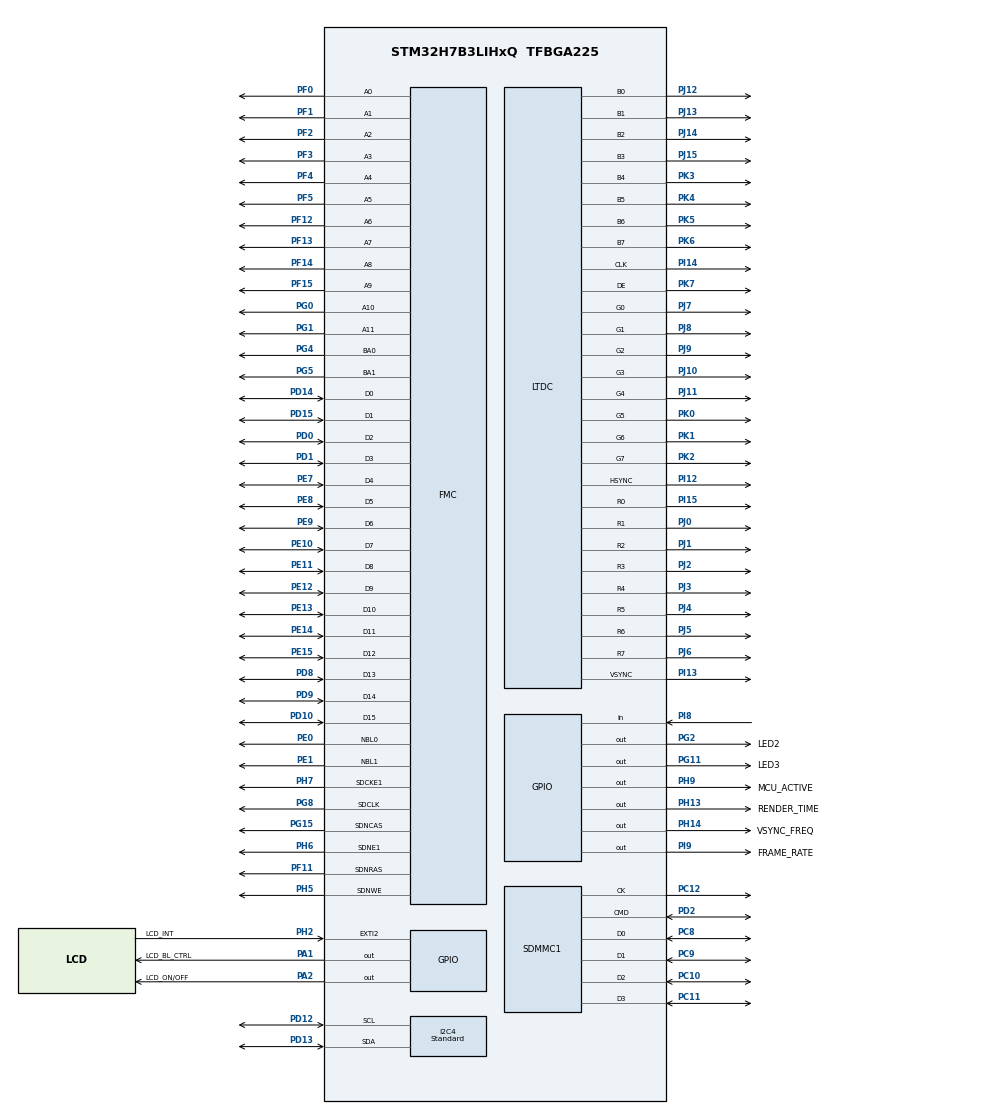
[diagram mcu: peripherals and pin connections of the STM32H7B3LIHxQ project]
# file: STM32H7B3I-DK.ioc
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CORTEX_M7.AccessPermission-Cortex_Memory_Protection_Unit_Region1_Settings=MPU_REGION_FULL_ACCESS
CORTEX_M7.AccessPermission-Cortex_Memory_Protection_Unit_Region2_Settings=MPU_REGION_FULL_ACCESS
CORTEX_M7.AccessPermission-Cortex_Memory_Protection_Unit_Region3_Settings=MPU_REGION_FULL_ACCESS
CORTEX_M7.BaseAddress-Cortex_Memory_Protection_Unit_Region0_Settings=0x90000000
CORTEX_M7.BaseAddress-Cortex_Memory_Protection_Unit_Region1_Settings=0x90000000
CORTEX_M7.BaseAddress-Cortex_Memory_Protection_Unit_Region2_Settings=0x24000000
CORTEX_M7.BaseAddress-Cortex_Memory_Protection_Unit_Region3_Settings=0x24000000
CORTEX_M7.CPU_DCache=Enabled
CORTEX_M7.CPU_ICache=Enabled
CORTEX_M7.DisableExec-Cortex_Memory_Protection_Unit_Region0_Settings=MPU_INSTRUCTION_ACCESS_DISABLE
CORTEX_M7.DisableExec-Cortex_Memory_Protection_Unit_Region1_Settings=MPU_INSTRUCTION_ACCESS_DISABLE
CORTEX_M7.DisableExec-Cortex_Memory_Protection_Unit_Region2_Settings=MPU_INSTRUCTION_ACCESS_DISABLE
CORTEX_M7.DisableExec-Cortex_Memory_Protection_Unit_Region3_Settings=MPU_INSTRUCTION_ACCESS_DISABLE
CORTEX_M7.Enable-Cortex_Memory_Protection_Unit_Region0_Settings=MPU_REGION_ENABLE
CORTEX_M7.Enable-Cortex_Memory_Protection_Unit_Region1_Settings=MPU_REGION_ENABLE
CORTEX_M7.Enable-Cortex_Memory_Protection_Unit_Region2_Settings=MPU_REGION_ENABLE
CORTEX_M7.Enable-Cortex_Memory_Protection_Unit_Region3_Settings=MPU_REGION_ENABLE
CORTEX_M7.IsBufferable-Cortex_Memory_Protection_Unit_Region3_Settings=MPU_ACCESS_BUFFERABLE
CORTEX_M7.IsCacheable-Cortex_Memory_Protection_Unit_Region1_Settings=MPU_ACCESS_CACHEABLE
CORTEX_M7.IsCacheable-Cortex_Memory_Protection_Unit_Region2_Settings=MPU_ACCESS_CACHEABLE
CORTEX_M7.IsCacheable-Cortex_Memory_Protection_Unit_Region3_Settings=MPU_ACCESS_CACHEABLE
CORTEX_M7.MPU_Control=MPU_PRIVILEGED_DEFAULT
CORTEX_M7.Size-Cortex_Memory_Protection_Unit_Region0_Settings=MPU_REGION_SIZE_256MB
CORTEX_M7.Size-Cortex_Memory_Protection_Unit_Region1_Settings=MPU_REGION_SIZE_64MB
CORTEX_M7.Size-Cortex_Memory_Protection_Unit_Region2_Settings=MPU_REGION_SIZE_1MB
CORTEX_M7.Size-Cortex_Memory_Protection_Unit_Region3_Settings=MPU_REGION_SIZE_256KB
DMA2D.ColorMode=DMA2D_OUTPUT_RGB565
FATFS.BSP.number=1
FATFS0.BSP.STBoard=false
FATFS0.BSP.api=Unknown
FATFS0.BSP.instance=PI8
FATFS0.BSP.ip=GPIO
FATFS0.BSP.mode=Input
FATFS0.BSP.name=Detect_SDIO
FATFS0.BSP.solution=PI8
FMC.CASLatency1=FMC_SDRAM_CAS_LATENCY_2
FMC.ColumnBitsNumber1=FMC_SDRAM_COLUMN_BITS_NUM_9
FMC.ExitSelfRefreshDelay1=7
FMC.LoadToActiveDelay1=2
FMC.RCDDelay1=2
FMC.RPDelay1=2
FMC.ReadBurst1=FMC_SDRAM_RBURST_ENABLE
FMC.ReadPipeDelay1=FMC_SDRAM_RPIPE_DELAY_2
FMC.RowCycleDelay1=7
FMC.SDClockPeriod1=FMC_SDRAM_CLOCK_PERIOD_3
FMC.SelfRefreshTime1=4
FMC.WriteRecoveryTime1=3
FREERTOS.Tasks01=defaultTask,24,128,StartDefaultTask,Default,NULL,Dynamic,NULL,NULL;GUI_Task,24,8192,TouchGFX_Task,As external,NULL,Dynamic,NULL,NULL;videoTask,8,1000,videoTaskFunc,As external,NULL,Dynamic,NULL,NULL
FREERTOS.configTOTAL_HEAP_SIZE=100000
FREERTOS.configUSE_APPLICATION_TASK_TAG=1
FREERTOS.configUSE_IDLE_HOOK=1
FREERTOS.configUSE_NEWLIB_REENTRANT=1
I2C4.Analog_Filter=I2C_ANALOGFILTER_DISABLE
I2C4.I2C_Fall_Time=0
I2C4.I2C_Rise_Time=0
I2C4.I2C_Speed_Mode=I2C_Standard
I2C4.Speed=100
I2C4.Timing=0x00C0EFFF
JPEG.JPEG_RGB_FORMAT=JPEG_RGB888
LTDC.ActiveH=272
LTDC.ActiveW=480
LTDC.Alpha0_L0=0
LTDC.Alpha_L0=255
LTDC.BlendingFactor1_L0=LTDC_BLENDING_FACTOR1_CA
LTDC.BlendingFactor2_L0=LTDC_BLENDING_FACTOR2_CA
LTDC.Blue=0
LTDC.Blue_L0=255
LTDC.FBStartAdress_L0=0xD0000000
LTDC.HBP=2
LTDC.HFP=32
LTDC.HSync=41
LTDC.ImageHeight_L0=272
LTDC.ImageWidth_L0=480
LTDC.Layers=0
LTDC.PixelFormat_L0=LTDC_PIXEL_FORMAT_RGB888
LTDC.VBP=2
LTDC.VFP=2
LTDC.VSync=10
LTDC.WindowX1_L0=480
LTDC.WindowY1_L0=272
Mcu.Family=STM32H7
Mcu.Name=STM32H7B3LIHxQ
Mcu.Package=TFBGA225
Mdma.MDMA_Channel0.Request0=SDMMC1_END_DATA
Mdma.MDMA_Channel0.RequestsNb=1
Mdma.MDMA_Channel0.SDMMC1_END_DATA.0.BlockCount=0
Mdma.MDMA_Channel0.SDMMC1_END_DATA.0.BlockDataLength=0
Mdma.MDMA_Channel0.SDMMC1_END_DATA.0.BufferTransferLength=512
Mdma.MDMA_Channel0.SDMMC1_END_DATA.0.CircularMode=MDMA_LINEAR_LIST
Mdma.MDMA_Channel0.SDMMC1_END_DATA.0.DataAlignment=MDMA_DATAALIGN_PACKENABLE
Mdma.MDMA_Channel0.SDMMC1_END_DATA.0.DestBlockAddressOffset=0
Mdma.MDMA_Channel0.SDMMC1_END_DATA.0.DestBurst=MDMA_DEST_BURST_SINGLE
Mdma.MDMA_Channel0.SDMMC1_END_DATA.0.DestDataSize=MDMA_DEST_DATASIZE_BYTE
Mdma.MDMA_Channel0.SDMMC1_END_DATA.0.DestinationInc=MDMA_DEST_INC_BYTE
Mdma.MDMA_Channel0.SDMMC1_END_DATA.0.DstAddress=0
Mdma.MDMA_Channel0.SDMMC1_END_DATA.0.Endianness=MDMA_LITTLE_ENDIANNESS_PRESERVE
Mdma.MDMA_Channel0.SDMMC1_END_DATA.0.Instance=MDMA_Channel0
Mdma.MDMA_Channel0.SDMMC1_END_DATA.0.MaskAddress=0
Mdma.MDMA_Channel0.SDMMC1_END_DATA.0.MaskData=0
Mdma.MDMA_Channel0.SDMMC1_END_DATA.0.Priority=MDMA_PRIORITY_LOW
Mdma.MDMA_Channel0.SDMMC1_END_DATA.0.Rank=First
Mdma.MDMA_Channel0.SDMMC1_END_DATA.0.SourceBlockAddressOffset=0
Mdma.MDMA_Channel0.SDMMC1_END_DATA.0.SourceBurst=MDMA_SOURCE_BURST_SINGLE
Mdma.MDMA_Channel0.SDMMC1_END_DATA.0.SourceDataSize=MDMA_SRC_DATASIZE_BYTE
Mdma.MDMA_Channel0.SDMMC1_END_DATA.0.SourceInc=MDMA_SRC_INC_BYTE
Mdma.MDMA_Channel0.SDMMC1_END_DATA.0.SrcAddress=0
Mdma.MDMA_Channel0.SDMMC1_END_DATA.0.TransferTriggerMode=MDMA_BUFFER_TRANSFER
Mdma.MDMA_Channel6.JPEG_OUTFIFO_TH.0.BlockCount=0
Mdma.MDMA_Channel6.JPEG_OUTFIFO_TH.0.BlockDataLength=0
Mdma.MDMA_Channel6.JPEG_OUTFIFO_TH.0.BufferTransferLength=32
Mdma.MDMA_Channel6.JPEG_OUTFIFO_TH.0.CircularMode=MDMA_LINEAR_LIST
Mdma.MDMA_Channel6.JPEG_OUTFIFO_TH.0.DataAlignment=MDMA_DATAALIGN_PACKENABLE
Mdma.MDMA_Channel6.JPEG_OUTFIFO_TH.0.DestBlockAddressOffset=0
Mdma.MDMA_Channel6.JPEG_OUTFIFO_TH.0.DestBurst=MDMA_DEST_BURST_32BEATS
Mdma.MDMA_Channel6.JPEG_OUTFIFO_TH.0.DestDataSize=MDMA_DEST_DATASIZE_BYTE
Mdma.MDMA_Channel6.JPEG_OUTFIFO_TH.0.DestinationInc=MDMA_DEST_INC_BYTE
Mdma.MDMA_Channel6.JPEG_OUTFIFO_TH.0.DstAddress=0
Mdma.MDMA_Channel6.JPEG_OUTFIFO_TH.0.Endianness=MDMA_LITTLE_ENDIANNESS_PRESERVE
Mdma.MDMA_Channel6.JPEG_OUTFIFO_TH.0.Instance=MDMA_Channel6
Mdma.MDMA_Channel6.JPEG_OUTFIFO_TH.0.MaskAddress=0
Mdma.MDMA_Channel6.JPEG_OUTFIFO_TH.0.MaskData=0
Mdma.MDMA_Channel6.JPEG_OUTFIFO_TH.0.Priority=MDMA_PRIORITY_VERY_HIGH
Mdma.MDMA_Channel6.JPEG_OUTFIFO_TH.0.Rank=First
Mdma.MDMA_Channel6.JPEG_OUTFIFO_TH.0.SourceBlockAddressOffset=0
Mdma.MDMA_Channel6.JPEG_OUTFIFO_TH.0.SourceBurst=MDMA_SOURCE_BURST_32BEATS
Mdma.MDMA_Channel6.JPEG_OUTFIFO_TH.0.SourceDataSize=MDMA_SRC_DATASIZE_WORD
Mdma.MDMA_Channel6.JPEG_OUTFIFO_TH.0.SourceInc=MDMA_SRC_INC_DISABLE
Mdma.MDMA_Channel6.JPEG_OUTFIFO_TH.0.SrcAddress=0
Mdma.MDMA_Channel6.JPEG_OUTFIFO_TH.0.TransferTriggerMode=MDMA_BUFFER_TRANSFER
Mdma.MDMA_Channel6.Request0=JPEG_OUTFIFO_TH
Mdma.MDMA_Channel6.RequestsNb=1
Mdma.MDMA_Channel7.JPEG_INFIFO_TH.0.BlockCount=0
Mdma.MDMA_Channel7.JPEG_INFIFO_TH.0.BlockDataLength=0
Mdma.MDMA_Channel7.JPEG_INFIFO_TH.0.BufferTransferLength=32
Mdma.MDMA_Channel7.JPEG_INFIFO_TH.0.CircularMode=MDMA_LINEAR_LIST
Mdma.MDMA_Channel7.JPEG_INFIFO_TH.0.DataAlignment=MDMA_DATAALIGN_PACKENABLE
Mdma.MDMA_Channel7.JPEG_INFIFO_TH.0.DestBlockAddressOffset=0
Mdma.MDMA_Channel7.JPEG_INFIFO_TH.0.DestBurst=MDMA_DEST_BURST_16BEATS
Mdma.MDMA_Channel7.JPEG_INFIFO_TH.0.DestDataSize=MDMA_DEST_DATASIZE_WORD
Mdma.MDMA_Channel7.JPEG_INFIFO_TH.0.DestinationInc=MDMA_DEST_INC_DISABLE
Mdma.MDMA_Channel7.JPEG_INFIFO_TH.0.DstAddress=0
Mdma.MDMA_Channel7.JPEG_INFIFO_TH.0.Endianness=MDMA_LITTLE_ENDIANNESS_PRESERVE
Mdma.MDMA_Channel7.JPEG_INFIFO_TH.0.Instance=MDMA_Channel7
Mdma.MDMA_Channel7.JPEG_INFIFO_TH.0.MaskAddress=0
Mdma.MDMA_Channel7.JPEG_INFIFO_TH.0.MaskData=0
Mdma.MDMA_Channel7.JPEG_INFIFO_TH.0.Priority=MDMA_PRIORITY_HIGH
Mdma.MDMA_Channel7.JPEG_INFIFO_TH.0.Rank=First
Mdma.MDMA_Channel7.JPEG_INFIFO_TH.0.SourceBlockAddressOffset=0
Mdma.MDMA_Channel7.JPEG_INFIFO_TH.0.SourceBurst=MDMA_SOURCE_BURST_32BEATS
Mdma.MDMA_Channel7.JPEG_INFIFO_TH.0.SourceDataSize=MDMA_SRC_DATASIZE_BYTE
Mdma.MDMA_Channel7.JPEG_INFIFO_TH.0.SourceInc=MDMA_SRC_INC_BYTE
Mdma.MDMA_Channel7.JPEG_INFIFO_TH.0.SrcAddress=0
Mdma.MDMA_Channel7.JPEG_INFIFO_TH.0.TransferTriggerMode=MDMA_BUFFER_TRANSFER
Mdma.MDMA_Channel7.Request0=JPEG_INFIFO_TH
Mdma.MDMA_Channel7.RequestsNb=1
Mdma.RequestSet0=MDMA_Channel7
Mdma.RequestSet1=MDMA_Channel6
Mdma.RequestSet2=MDMA_Channel0
Mdma.RequestSetsNb=3
NVIC.DMA2D_IRQn=true\:5\:0\:true\:false\:true\:false\:true\:true\:true
NVIC.EXTI2_IRQn=true\:5\:0\:false\:false\:true\:true\:true\:true\:true
NVIC.JPEG_IRQn=true\:5\:0\:false\:false\:true\:true\:true\:true\:true
NVIC.LTDC_IRQn=true\:5\:0\:false\:false\:true\:true\:true\:true\:true
NVIC.MDMA_IRQn=true\:5\:0\:false\:false\:true\:true\:false\:true\:true
NVIC.OCTOSPI1_IRQn=true\:5\:0\:false\:false\:true\:true\:true\:true\:true
NVIC.PriorityGroup=NVIC_PRIORITYGROUP_4
NVIC.SDMMC1_IRQn=true\:5\:0\:false\:false\:true\:true\:true\:true\:true
NVIC.TIM6_DAC_IRQn=true\:0\:0\:false\:false\:true\:false\:false\:true\:true
NVIC.TimeBase=TIM6_DAC_IRQn
NVIC.TimeBaseIP=TIM6
OCTOSPI1.ChipSelectBoundary=0
OCTOSPI1.ChipSelectHighTime=2
OCTOSPI1.ClockPrescaler=3
OCTOSPI1.DeviceSize=26
OCTOSPI1.Refresh=0
PA1.GPIO_Label=LCD_BL_CTRL
PA1.GPIO_ModeDefaultOutputPP=GPIO_MODE_OUTPUT_PP
PA1.GPIO_PuPd=GPIO_NOPULL
PA1.GPIO_Speed=GPIO_SPEED_FREQ_LOW
PA1.PinState=GPIO_PIN_RESET
PA1.Signal=GPIO_Output
PA13.Mode=JTAG_4_pins
PA13.Signal=DEBUG_JTMS-SWDIO
PA14.Mode=JTAG_4_pins
PA14.Signal=DEBUG_JTCK-SWCLK
PA15.Mode=JTAG_4_pins
PA15.Signal=DEBUG_JTDI
PA2.GPIO_Label=LCD_ON/OFF
PA2.GPIO_ModeDefaultOutputPP=GPIO_MODE_OUTPUT_PP
PA2.GPIO_PuPd=GPIO_PULLUP
PA2.GPIO_Speed=GPIO_SPEED_FREQ_LOW
PA2.PinState=GPIO_PIN_RESET
PA2.Signal=GPIO_Output
PB3.Mode=JTAG_4_pins
PB3.Signal=DEBUG_JTDO-SWO
PC10.Mode=SD_4_bits_Wide_bus
PC10.Signal=SDMMC1_D2
PC11.Mode=SD_4_bits_Wide_bus
PC11.Signal=SDMMC1_D3
PC12.Mode=SD_4_bits_Wide_bus
PC12.Signal=SDMMC1_CK
PC8.Mode=SD_4_bits_Wide_bus
PC8.Signal=SDMMC1_D0
PC9.Mode=SD_4_bits_Wide_bus
PC9.Signal=SDMMC1_D1
PD0.Signal=FMC_D2_DA2
PD1.Signal=FMC_D3_DA3
PD10.Signal=FMC_D15_DA15
PD12.GPIO_Pu=GPIO_PULLUP
PD12.GPIO_Speed=GPIO_SPEED_FREQ_HIGH
PD12.Mode=I2C
PD12.Signal=I2C4_SCL
PD13.GPIO_Pu=GPIO_PULLUP
PD13.GPIO_Speed=GPIO_SPEED_FREQ_HIGH
PD13.Mode=I2C
PD13.Signal=I2C4_SDA
PD14.Signal=FMC_D0_DA0
PD15.Signal=FMC_D1_DA1
PD2.Mode=SD_4_bits_Wide_bus
PD2.Signal=SDMMC1_CMD
PD8.Signal=FMC_D13_DA13
PD9.Signal=FMC_D14_DA14
PE0.Signal=FMC_NBL0
PE1.Signal=FMC_NBL1
PE10.Signal=FMC_D7_DA7
PE11.Signal=FMC_D8_DA8
PE12.Signal=FMC_D9_DA9
PE13.Signal=FMC_D10_DA10
PE14.Signal=FMC_D11_DA11
PE15.Signal=FMC_D12_DA12
PE7.Signal=FMC_D4_DA4
PE8.Signal=FMC_D5_DA5
PE9.Signal=FMC_D6_DA6
PF0.Signal=FMC_A0
PF1.Signal=FMC_A1
PF11.Signal=FMC_SDNRAS
PF12.Signal=FMC_A6
PF13.Signal=FMC_A7
PF14.Signal=FMC_A8
PF15.Signal=FMC_A9
PF2.Signal=FMC_A2
PF3.Signal=FMC_A3
PF4.Signal=FMC_A4
PF5.Signal=FMC_A5
PG0.Signal=FMC_A10
PG1.Signal=FMC_A11
PG11.GPIO_Label=LED3
PG11.PinState=GPIO_PIN_SET
PG11.Signal=GPIO_Output
PG15.Signal=FMC_SDNCAS
PG2.GPIO_Label=LED2
PG2.PinState=GPIO_PIN_SET
PG2.Signal=GPIO_Output
PG4.Signal=FMC_A14_BA0
PG5.Signal=FMC_A15_BA1
PG8.Signal=FMC_SDCLK
PH0-OSC_IN.Mode=HSE-External-Oscillator
PH0-OSC_IN.Signal=RCC_OSC_IN
PH1-OSC_OUT.Mode=HSE-External-Oscillator
PH1-OSC_OUT.Signal=RCC_OSC_OUT
PH13.GPIO_Label=RENDER_TIME
PH13.GPIO_Speed=GPIO_SPEED_FREQ_VERY_HIGH
PH13.Signal=GPIO_Output
PH14.GPIO_Label=VSYNC_FREQ
PH14.GPIO_Speed=GPIO_SPEED_FREQ_VERY_HIGH
PH14.Signal=GPIO_Output
PH2.GPIO_Label=LCD_INT
PH2.GPIO_PuPd=GPIO_PULLUP
PH2.Signal=GPXTI2
PH5.Signal=FMC_SDNWE
PH6.Mode=SdramChipSelect2_1
PH6.Signal=FMC_SDNE1
PH7.Mode=SdramChipSelect2_1
PH7.Signal=FMC_SDCKE1
PH9.GPIO_Label=MCU_ACTIVE
PH9.GPIO_Speed=GPIO_SPEED_FREQ_VERY_HIGH
PH9.Signal=GPIO_Output
PI12.Mode=RGB888
PI12.Signal=LTDC_HSYNC
PI13.Mode=RGB888
PI13.Signal=LTDC_VSYNC
PI14.Mode=RGB888
PI14.Signal=LTDC_CLK
PI15.Mode=RGB888
PI15.Signal=LTDC_R0
PI8.GPIO_PuPd=GPIO_PULLUP
PI8.Signal=GPIO_Input
PI9.GPIO_Label=FRAME_RATE
PI9.GPIO_Speed=GPIO_SPEED_FREQ_VERY_HIGH
PI9.Signal=GPIO_Output
PJ0.Mode=RGB888
PJ0.Signal=LTDC_R1
PJ1.Mode=RGB888
PJ1.Signal=LTDC_R2
PJ10.Mode=RGB888
PJ10.Signal=LTDC_G3
PJ11.Mode=RGB888
PJ11.Signal=LTDC_G4
PJ12.Mode=RGB888
PJ12.Signal=LTDC_B0
PJ13.Mode=RGB888
PJ13.Signal=LTDC_B1
PJ14.Mode=RGB888
PJ14.Signal=LTDC_B2
PJ15.Mode=RGB888
PJ15.Signal=LTDC_B3
PJ2.Mode=RGB888
PJ2.Signal=LTDC_R3
PJ3.Mode=RGB888
PJ3.Signal=LTDC_R4
PJ4.Mode=RGB888
PJ4.Signal=LTDC_R5
PJ5.Mode=RGB888
PJ5.Signal=LTDC_R6
PJ6.Mode=RGB888
PJ6.Signal=LTDC_R7
PJ7.Mode=RGB888
PJ7.Signal=LTDC_G0
PJ8.Mode=RGB888
PJ8.Signal=LTDC_G1
PJ9.Mode=RGB888
PJ9.Signal=LTDC_G2
PK0.Mode=RGB888
PK0.Signal=LTDC_G5
PK1.Mode=RGB888
PK1.Signal=LTDC_G6
PK2.Mode=RGB888
PK2.Signal=LTDC_G7
PK3.Mode=RGB888
PK3.Signal=LTDC_B4
PK4.Mode=RGB888
PK4.Signal=LTDC_B5
PK5.Mode=RGB888
PK5.Signal=LTDC_B6
PK6.Mode=RGB888
PK6.Signal=LTDC_B7
PK7.GPIO_PuPd=GPIO_NOPULL
PK7.Mode=RGB888
PK7.Signal=LTDC_DE
ProjectManager.HeapSize=0x1000
ProjectManager.StackSize=0x1000
ProjectManager.TargetToolchain=STM32CubeIDE
RCC.ADCFreq_Value=100000000
RCC.APB1Freq_Value=50000000
RCC.APB2Freq_Value=50000000
RCC.APB3Freq_Value=50000000
RCC.APB4Freq_Value=50000000
RCC.CKPERSourceSelection=RCC_CLKPSOURCE_HSE
RCC.CortexFreq_Value=100000000
RCC.DIVM1=4
RCC.DIVM2=4
RCC.DIVM3=24
RCC.DIVN1=25
RCC.DIVN2=25
RCC.DIVN3=201
RCC.DIVR3=21
RCC.HCLKFreq_Value=50000000
RCC.HPRE=RCC_HCLK_DIV2
RCC.HSIDiv=RCC_PLLSAIDIVR_2
RCC.QSPICLockSelection=RCC_OSPICLKSOURCE_PLL2
RCC.SYSCLKFreq_VALUE=100000000
RCC.SYSCLKSource=RCC_SYSCLKSOURCE_PLLCLK
RCC.SupplySource=PWR_DIRECT_SMPS_SUPPLY
RCC.USBFreq_Value=100000000
SDMMC1.ClockDiv=1
SDMMC1.ClockPowerSave=SDMMC_CLOCK_POWER_SAVE_ENABLE
SDMMC1.HardwareFlowControl=SDMMC_HARDWARE_FLOW_CONTROL_ENABLE
SDMMC1.TransceiverPresent=SDMMC_TRANSCEIVER_NOT_PRESENT
SH.FMC_A0.0=FMC_A0,12b-sda1
SH.FMC_A1.0=FMC_A1,12b-sda1
SH.FMC_A10.0=FMC_A10,12b-sda1
SH.FMC_A11.0=FMC_A11,12b-sda1
SH.FMC_A14_BA0.0=FMC_BA0,FourSdramBanks1
SH.FMC_A15_BA1.0=FMC_BA1,FourSdramBanks1
SH.FMC_A2.0=FMC_A2,12b-sda1
SH.FMC_A3.0=FMC_A3,12b-sda1
SH.FMC_A4.0=FMC_A4,12b-sda1
SH.FMC_A5.0=FMC_A5,12b-sda1
SH.FMC_A6.0=FMC_A6,12b-sda1
SH.FMC_A7.0=FMC_A7,12b-sda1
SH.FMC_A8.0=FMC_A8,12b-sda1
SH.FMC_A9.0=FMC_A9,12b-sda1
SH.FMC_D0_DA0.0=FMC_D0,sd-16b-d1
SH.FMC_D10_DA10.0=FMC_D10,sd-16b-d1
SH.FMC_D11_DA11.0=FMC_D11,sd-16b-d1
SH.FMC_D12_DA12.0=FMC_D12,sd-16b-d1
SH.FMC_D13_DA13.0=FMC_D13,sd-16b-d1
SH.FMC_D14_DA14.0=FMC_D14,sd-16b-d1
SH.FMC_D15_DA15.0=FMC_D15,sd-16b-d1
SH.FMC_D1_DA1.0=FMC_D1,sd-16b-d1
SH.FMC_D2_DA2.0=FMC_D2,sd-16b-d1
SH.FMC_D3_DA3.0=FMC_D3,sd-16b-d1
SH.FMC_D4_DA4.0=FMC_D4,sd-16b-d1
SH.FMC_D5_DA5.0=FMC_D5,sd-16b-d1
SH.FMC_D6_DA6.0=FMC_D6,sd-16b-d1
SH.FMC_D7_DA7.0=FMC_D7,sd-16b-d1
SH.FMC_D8_DA8.0=FMC_D8,sd-16b-d1
SH.FMC_D9_DA9.0=FMC_D9,sd-16b-d1
SH.FMC_NBL0.0=FMC_NBL0,Sd2ByteEnable1
SH.FMC_NBL1.0=FMC_NBL1,Sd2ByteEnable1
SH.FMC_SDCLK.0=FMC_SDCLK,12b-sda1
SH.FMC_SDNCAS.0=FMC_SDNCAS,12b-sda1
SH.FMC_SDNRAS.0=FMC_SDNRAS,12b-sda1
SH.FMC_SDNWE.0=FMC_SDNWE,12b-sda1
STMicroelectronics.X-CUBE-TOUCHGFX.4.24.0.ApplicationCcGraphicsJjApplication=TouchGFXOoGenerator
STMicroelectronics.X-CUBE-TOUCHGFX.4.24.0.tgfx_buffering_strategy=Double
STMicroelectronics.X-CUBE-TOUCHGFX.4.24.0.tgfx_display_interface=disp_ltdc
STMicroelectronics.X-CUBE-TOUCHGFX.4.24.0.tgfx_hardware_accelerator=dma_2d
STMicroelectronics.X-CUBE-TOUCHGFX.4.24.0.tgfx_vector_fonts=Enabled
STMicroelectronics.X-CUBE-TOUCHGFX.4.24.0.tgfx_vector_rendering=Software
STMicroelectronics.X-CUBE-TOUCHGFX.4.24.0.tgfx_video=Hardware
STMicroelectronics.X-CUBE-TOUCHGFX.4.24.0.tgfx_video_buffer_format=RGB888\:3
STMicroelectronics.X-CUBE-TOUCHGFX.4.24.0.tgfx_video_height=272
STMicroelectronics.X-CUBE-TOUCHGFX.4.24.0.tgfx_video_strategy=1
STMicroelectronics.X-CUBE-TOUCHGFX.4.24.0.tgfx_video_width=480
STMicroelectronics.X-CUBE-TOUCHGFX.4.24.0.tgfx_vsync=vsync_ltdc
VP_CRC_VS_CRC.Mode=CRC_Activate
VP_DMA2D_VS_DMA2D.Mode=DMA2D_Activate
VP_FATFS_VS_SDIO.Mode=SDIO
VP_FREERTOS_VS_CMSIS_V2.Mode=CMSIS_V2
VP_JPEG_VS_JPEG.Mode=JPEG_Activate
VP_LIBJPEG_VS_JPEGLIB.Mode=Enabled
VP_OCTOSPI1_VS_octo.Mode=octo_mode
VP_STMicroelectronics.X-CUBE-TOUCHGFX_VS_GraphicsJjApplication_4.24.0.Mode=GraphicsJjApplication
VP_SYS_VS_tim6.Mode=TIM6
board=custom

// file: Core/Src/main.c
/* USER CODE BEGIN Header */
/**
  ******************************************************************************
  * @file           : main.c
  * @brief          : Main program body
  ******************************************************************************
  * @attention
  *
  * <h2><center>&copy; Copyright (c) 2019 STMicroelectronics.
  * All rights reserved.</center></h2>
  *
  * This software component is licensed by ST under Ultimate Liberty license
  * SLA0044, the "License"; You may not use this file except in compliance with
  * the License. You may obtain a copy of the License at:
  *                             www.st.com/SLA0044
  *
  ******************************************************************************
  */
/* USER CODE END Header */
#include "main.h"
#include "cmsis_os.h"
#include "fatfs.h"
#include "libjpeg.h"
#include "app_touchgfx.h"

/* USER CODE BEGIN Includes */
#include "stm32h7b3i_discovery_ospi.h"
/* USER CODE END Includes */

CRC_HandleTypeDef hcrc;

DMA2D_HandleTypeDef hdma2d;

I2C_HandleTypeDef hi2c4;

JPEG_HandleTypeDef hjpeg;
MDMA_HandleTypeDef hmdma_jpeg_infifo_th;
MDMA_HandleTypeDef hmdma_jpeg_outfifo_th;

LTDC_HandleTypeDef hltdc;

OSPI_HandleTypeDef hospi1;

SD_HandleTypeDef hsd1;

MDMA_HandleTypeDef hmdma_mdma_channel0_sdmmc1_end_data_0;
SDRAM_HandleTypeDef hsdram1;

/* Definitions for defaultTask */
osThreadId_t defaultTaskHandle;
const osThreadAttr_t defaultTask_attributes = {
  .name = "defaultTask",
  .stack_size = 128 * 4,
  .priority = (osPriority_t) osPriorityNormal,
};
/* Definitions for GUI_Task */
osThreadId_t GUI_TaskHandle;
const osThreadAttr_t GUI_Task_attributes = {
  .name = "GUI_Task",
  .stack_size = 8192 * 4,
  .priority = (osPriority_t) osPriorityNormal,
};
/* Definitions for videoTask */
osThreadId_t videoTaskHandle;
const osThreadAttr_t videoTask_attributes = {
  .name = "videoTask",
  .stack_size = 1000 * 4,
  .priority = (osPriority_t) osPriorityLow,
};

/*osThreadId_t SD_TaskHandle;
const osThreadAttr_t SD_Task_attributes = {
  .name = "SD_Task",
  .stack_size = 1000 * 4,
  .priority = (osPriority_t) osPriorityHigh,
};*/
/* USER CODE BEGIN PV */
FMC_SDRAM_CommandTypeDef command;

/* USER CODE END PV */

void SystemClock_Config(void);
static void MPU_Config(void);
static void MX_GPIO_Init(void);
static void MX_MDMA_Init(void);
static void MX_DMA2D_Init(void);
static void MX_LTDC_Init(void);
static void MX_I2C4_Init(void);
static void MX_OCTOSPI1_Init(void);
static void MX_FMC_Init(void);
static void MX_CRC_Init(void);
static void MX_JPEG_Init(void);
static void MX_SDMMC1_SD_Init(void);
void StartDefaultTask(void *argument);
//void StartSD_Task(void *argument);
extern void TouchGFX_Task(void *argument);
extern void videoTaskFunc(void *argument);

/* USER CODE BEGIN PFP */
static void SDRAM_Initialization_Sequence(SDRAM_HandleTypeDef *hsdram, FMC_SDRAM_CommandTypeDef *Command);

/* USER CODE END PFP */

int main(void)
{

  /* MPU Configuration--------------------------------------------------------*/
  MPU_Config();

  /* Enable the CPU Cache */

  /* Enable I-Cache---------------------------------------------------------*/
  SCB_EnableICache();

  /* Enable D-Cache---------------------------------------------------------*/
  SCB_EnableDCache();
  //SCB_DisableDCache();

  /* MCU Configuration--------------------------------------------------------*/

  /* Reset of all peripherals, Initializes the Flash interface and the Systick. */
  HAL_Init();

  /* Configure the system clock */
  SystemClock_Config();

  /* Initialize all configured peripherals */
  MX_GPIO_Init();
  MX_MDMA_Init();
  MX_DMA2D_Init();
  MX_LTDC_Init();
  MX_I2C4_Init();
  MX_OCTOSPI1_Init();
  MX_FMC_Init();
  MX_CRC_Init();
  MX_JPEG_Init();
  MX_LIBJPEG_Init();
  MX_SDMMC1_SD_Init();
  MX_FATFS_Init();
  MX_TouchGFX_Init();
  /* Call PreOsInit function */
  MX_TouchGFX_PreOSInit();
  /* USER CODE BEGIN 2 */
  SDRAM_Initialization_Sequence(&hsdram1, &command);

  /* USER CODE END 2 */

  /* Init scheduler */
  osKernelInitialize();

  /* Create the thread(s) */
  /* creation of defaultTask */
  defaultTaskHandle = osThreadNew(StartDefaultTask, NULL, &defaultTask_attributes);
  //SD_TaskHandle = osThreadNew(StartSD_Task, NULL, &SD_Task_attributes);
  /* creation of GUI_Task */
  GUI_TaskHandle = osThreadNew(TouchGFX_Task, NULL, &GUI_Task_attributes);

  /* creation of videoTask */
  videoTaskHandle = osThreadNew(videoTaskFunc, NULL, &videoTask_attributes);

  /* Start scheduler */
  osKernelStart();

  /* We should never get here as control is now taken by the scheduler */

  /* Infinite loop */
  while (1)
  {

  }
}

void SystemClock_Config(void)
{
  RCC_OscInitTypeDef RCC_OscInitStruct = {0};
  RCC_ClkInitTypeDef RCC_ClkInitStruct = {0};

  /*AXI clock gating */
  RCC->CKGAENR = 0xFFFFFFFF;

  /** Supply configuration update enable
  */
  HAL_PWREx_ConfigSupply(PWR_DIRECT_SMPS_SUPPLY);

  /** Configure the main internal regulator output voltage
  */
  __HAL_PWR_VOLTAGESCALING_CONFIG(PWR_REGULATOR_VOLTAGE_SCALE2);

  while(!__HAL_PWR_GET_FLAG(PWR_FLAG_VOSRDY)) {}

  /** Initializes the RCC Oscillators according to the specified parameters
  * in the RCC_OscInitTypeDef structure.
  */
  RCC_OscInitStruct.OscillatorType = RCC_OSCILLATORTYPE_HSI;
  RCC_OscInitStruct.HSIState = RCC_HSI_DIV2;
  RCC_OscInitStruct.HSICalibrationValue = 64;
  RCC_OscInitStruct.PLL.PLLState = RCC_PLL_ON;
  RCC_OscInitStruct.PLL.PLLSource = RCC_PLLSOURCE_HSI;
  RCC_OscInitStruct.PLL.PLLM = 4;
  RCC_OscInitStruct.PLL.PLLN = 25;
  RCC_OscInitStruct.PLL.PLLP = 2;
  RCC_OscInitStruct.PLL.PLLQ = 2;
  RCC_OscInitStruct.PLL.PLLR = 2;
  RCC_OscInitStruct.PLL.PLLRGE = RCC_PLL1VCIRANGE_3;
  RCC_OscInitStruct.PLL.PLLVCOSEL = RCC_PLL1VCOWIDE;
  RCC_OscInitStruct.PLL.PLLFRACN = 0;
  if (HAL_RCC_OscConfig(&RCC_OscInitStruct) != HAL_OK)
  {
    Error_Handler();
  }

  /** Initializes the CPU, AHB and APB buses clocks
  */
  RCC_ClkInitStruct.ClockType = RCC_CLOCKTYPE_HCLK|RCC_CLOCKTYPE_SYSCLK
                              |RCC_CLOCKTYPE_PCLK1|RCC_CLOCKTYPE_PCLK2
                              |RCC_CLOCKTYPE_D3PCLK1|RCC_CLOCKTYPE_D1PCLK1;
  RCC_ClkInitStruct.SYSCLKSource = RCC_SYSCLKSOURCE_PLLCLK;
  RCC_ClkInitStruct.SYSCLKDivider = RCC_SYSCLK_DIV1;
  RCC_ClkInitStruct.AHBCLKDivider = RCC_HCLK_DIV2;
  RCC_ClkInitStruct.APB3CLKDivider = RCC_APB3_DIV1;
  RCC_ClkInitStruct.APB1CLKDivider = RCC_APB1_DIV1;
  RCC_ClkInitStruct.APB2CLKDivider = RCC_APB2_DIV1;
  RCC_ClkInitStruct.APB4CLKDivider = RCC_APB4_DIV1;

  if (HAL_RCC_ClockConfig(&RCC_ClkInitStruct, FLASH_LATENCY_1) != HAL_OK)
  {
    Error_Handler();
  }
}

static void MX_CRC_Init(void)
{

  hcrc.Instance = CRC;
  hcrc.Init.DefaultPolynomialUse = DEFAULT_POLYNOMIAL_ENABLE;
  hcrc.Init.DefaultInitValueUse = DEFAULT_INIT_VALUE_ENABLE;
  hcrc.Init.InputDataInversionMode = CRC_INPUTDATA_INVERSION_NONE;
  hcrc.Init.OutputDataInversionMode = CRC_OUTPUTDATA_INVERSION_DISABLE;
  hcrc.InputDataFormat = CRC_INPUTDATA_FORMAT_BYTES;
  if (HAL_CRC_Init(&hcrc) != HAL_OK)
  {
    Error_Handler();
  }

}

static void MX_DMA2D_Init(void)
{

  hdma2d.Instance = DMA2D;
  hdma2d.Init.Mode = DMA2D_M2M;
  hdma2d.Init.ColorMode = DMA2D_OUTPUT_RGB565;
  hdma2d.Init.OutputOffset = 0;
  hdma2d.LayerCfg[1].InputOffset = 0;
  hdma2d.LayerCfg[1].InputColorMode = DMA2D_INPUT_RGB565;
  hdma2d.LayerCfg[1].AlphaMode = DMA2D_NO_MODIF_ALPHA;
  hdma2d.LayerCfg[1].InputAlpha = 0;
  hdma2d.LayerCfg[1].AlphaInverted = DMA2D_REGULAR_ALPHA;
  hdma2d.LayerCfg[1].RedBlueSwap = DMA2D_RB_REGULAR;
  hdma2d.LayerCfg[1].ChromaSubSampling = DMA2D_NO_CSS;
  if (HAL_DMA2D_Init(&hdma2d) != HAL_OK)
  {
    Error_Handler();
  }
  if (HAL_DMA2D_ConfigLayer(&hdma2d, 1) != HAL_OK)
  {
    Error_Handler();
  }

}

static void MX_I2C4_Init(void)
{

  hi2c4.Instance = I2C4;
  hi2c4.Init.Timing = 0x00C0EFFF;
  hi2c4.Init.OwnAddress1 = 0;
  hi2c4.Init.AddressingMode = I2C_ADDRESSINGMODE_7BIT;
  hi2c4.Init.DualAddressMode = I2C_DUALADDRESS_DISABLE;
  hi2c4.Init.OwnAddress2 = 0;
  hi2c4.Init.OwnAddress2Masks = I2C_OA2_NOMASK;
  hi2c4.Init.GeneralCallMode = I2C_GENERALCALL_DISABLE;
  hi2c4.Init.NoStretchMode = I2C_NOSTRETCH_DISABLE;
  if (HAL_I2C_Init(&hi2c4) != HAL_OK)
  {
    Error_Handler();
  }

  /** Configure Analogue filter
  */
  if (HAL_I2CEx_ConfigAnalogFilter(&hi2c4, I2C_ANALOGFILTER_DISABLE) != HAL_OK)
  {
    Error_Handler();
  }

  /** Configure Digital filter
  */
  if (HAL_I2CEx_ConfigDigitalFilter(&hi2c4, 0) != HAL_OK)
  {
    Error_Handler();
  }

}

static void MX_JPEG_Init(void)
{

  hjpeg.Instance = JPEG;
  if (HAL_JPEG_Init(&hjpeg) != HAL_OK)
  {
    Error_Handler();
  }

}

static void MX_LTDC_Init(void)
{

  LTDC_LayerCfgTypeDef pLayerCfg = {0};

  hltdc.Instance = LTDC;
  hltdc.Init.HSPolarity = LTDC_HSPOLARITY_AL;
  hltdc.Init.VSPolarity = LTDC_VSPOLARITY_AL;
  hltdc.Init.DEPolarity = LTDC_DEPOLARITY_AL;
  hltdc.Init.PCPolarity = LTDC_PCPOLARITY_IPC;
  hltdc.Init.HorizontalSync = 40;
  hltdc.Init.VerticalSync = 9;
  hltdc.Init.AccumulatedHBP = 42;
  hltdc.Init.AccumulatedVBP = 11;
  hltdc.Init.AccumulatedActiveW = 522;
  hltdc.Init.AccumulatedActiveH = 283;
  hltdc.Init.TotalWidth = 554;
  hltdc.Init.TotalHeigh = 285;
  hltdc.Init.Backcolor.Blue = 0;
  hltdc.Init.Backcolor.Green = 0;
  hltdc.Init.Backcolor.Red = 0;
  if (HAL_LTDC_Init(&hltdc) != HAL_OK)
  {
    Error_Handler();
  }
  pLayerCfg.WindowX0 = 0;
  pLayerCfg.WindowX1 = 480;
  pLayerCfg.WindowY0 = 0;
  pLayerCfg.WindowY1 = 272;
  pLayerCfg.PixelFormat = LTDC_PIXEL_FORMAT_RGB888;
  pLayerCfg.Alpha = 255;
  pLayerCfg.Alpha0 = 0;
  pLayerCfg.BlendingFactor1 = LTDC_BLENDING_FACTOR1_CA;
  pLayerCfg.BlendingFactor2 = LTDC_BLENDING_FACTOR2_CA;
  pLayerCfg.FBStartAdress = 0xD0000000;
  pLayerCfg.ImageWidth = 480;
  pLayerCfg.ImageHeight = 272;
  pLayerCfg.Backcolor.Blue = 255;
  pLayerCfg.Backcolor.Green = 0;
  pLayerCfg.Backcolor.Red = 0;
  if (HAL_LTDC_ConfigLayer(&hltdc, &pLayerCfg, 0) != HAL_OK)
  {
    Error_Handler();
  }

}

static void MX_OCTOSPI1_Init(void)
{

  /* OCTOSPI1 parameter configuration*/
  hospi1.Instance = OCTOSPI1;
  hospi1.Init.FifoThreshold = 1;
  hospi1.Init.DualQuad = HAL_OSPI_DUALQUAD_DISABLE;
  hospi1.Init.MemoryType = HAL_OSPI_MEMTYPE_MICRON;
  hospi1.Init.DeviceSize = 26;
  hospi1.Init.ChipSelectHighTime = 2;
  hospi1.Init.FreeRunningClock = HAL_OSPI_FREERUNCLK_DISABLE;
  hospi1.Init.ClockMode = HAL_OSPI_CLOCK_MODE_0;
  hospi1.Init.WrapSize = HAL_OSPI_WRAP_NOT_SUPPORTED;
  hospi1.Init.ClockPrescaler = 3;
  hospi1.Init.SampleShifting = HAL_OSPI_SAMPLE_SHIFTING_NONE;
  hospi1.Init.DelayHoldQuarterCycle = HAL_OSPI_DHQC_DISABLE;
  hospi1.Init.ChipSelectBoundary = 0;
  hospi1.Init.DelayBlockBypass = HAL_OSPI_DELAY_BLOCK_BYPASSED;
  hospi1.Init.MaxTran = 0;
  hospi1.Init.Refresh = 0;
  if (HAL_OSPI_Init(&hospi1) != HAL_OK)
  {
    Error_Handler();
  }
  /* USER CODE BEGIN OCTOSPI1_Init 2 */
  BSP_OSPI_NOR_Init_t Flash;
  Flash.InterfaceMode = BSP_OSPI_NOR_OPI_MODE;
  Flash.TransferRate  = BSP_OSPI_NOR_DTR_TRANSFER;
  BSP_OSPI_NOR_DeInit(0);
  int32_t RetVal = BSP_OSPI_NOR_Init(0, &Flash);
  if(RetVal != BSP_ERROR_NONE)
  {
    Error_Handler();
  }
  RetVal = BSP_OSPI_NOR_EnableMemoryMappedMode(0);
  if(RetVal != BSP_ERROR_NONE)
  {
    Error_Handler();
  }
  /* USER CODE END OCTOSPI1_Init 2 */

}

static void MX_SDMMC1_SD_Init(void)
{

  hsd1.Instance = SDMMC1;
  hsd1.Init.ClockEdge = SDMMC_CLOCK_EDGE_RISING;
  hsd1.Init.ClockPowerSave = SDMMC_CLOCK_POWER_SAVE_ENABLE;
  hsd1.Init.BusWide = SDMMC_BUS_WIDE_4B;
  hsd1.Init.HardwareFlowControl = SDMMC_HARDWARE_FLOW_CONTROL_ENABLE;
  hsd1.Init.ClockDiv = 1;

}

/**
  * Enable MDMA controller clock
  * Configure MDMA for global transfers
  *   hmdma_mdma_channel0_sdmmc1_end_data_0
  */
static void MX_MDMA_Init(void)
{

  /* MDMA controller clock enable */
  __HAL_RCC_MDMA_CLK_ENABLE();
  /* Local variables */

  /* Configure MDMA channel MDMA_Channel0 */
  /* Configure MDMA request hmdma_mdma_channel0_sdmmc1_end_data_0 on MDMA_Channel0 */
  hmdma_mdma_channel0_sdmmc1_end_data_0.Instance = MDMA_Channel0;
  hmdma_mdma_channel0_sdmmc1_end_data_0.Init.Request = MDMA_REQUEST_SDMMC1_END_DATA;
  hmdma_mdma_channel0_sdmmc1_end_data_0.Init.TransferTriggerMode = MDMA_BUFFER_TRANSFER;
  hmdma_mdma_channel0_sdmmc1_end_data_0.Init.Priority = MDMA_PRIORITY_LOW;
  hmdma_mdma_channel0_sdmmc1_end_data_0.Init.Endianness = MDMA_LITTLE_ENDIANNESS_PRESERVE;
  hmdma_mdma_channel0_sdmmc1_end_data_0.Init.SourceInc = MDMA_SRC_INC_BYTE;
  hmdma_mdma_channel0_sdmmc1_end_data_0.Init.DestinationInc = MDMA_DEST_INC_BYTE;
  hmdma_mdma_channel0_sdmmc1_end_data_0.Init.SourceDataSize = MDMA_SRC_DATASIZE_BYTE;
  hmdma_mdma_channel0_sdmmc1_end_data_0.Init.DestDataSize = MDMA_DEST_DATASIZE_BYTE;
  hmdma_mdma_channel0_sdmmc1_end_data_0.Init.DataAlignment = MDMA_DATAALIGN_PACKENABLE;
  hmdma_mdma_channel0_sdmmc1_end_data_0.Init.BufferTransferLength = 512;
  hmdma_mdma_channel0_sdmmc1_end_data_0.Init.SourceBurst = MDMA_SOURCE_BURST_SINGLE;
  hmdma_mdma_channel0_sdmmc1_end_data_0.Init.DestBurst = MDMA_DEST_BURST_SINGLE;
  hmdma_mdma_channel0_sdmmc1_end_data_0.Init.SourceBlockAddressOffset = 0;
  hmdma_mdma_channel0_sdmmc1_end_data_0.Init.DestBlockAddressOffset = 0;
  if (HAL_MDMA_Init(&hmdma_mdma_channel0_sdmmc1_end_data_0) != HAL_OK)
  {
    Error_Handler();
  }

  /* Configure post request address and data masks */
  if (HAL_MDMA_ConfigPostRequestMask(&hmdma_mdma_channel0_sdmmc1_end_data_0, 0, 0) != HAL_OK)
  {
    Error_Handler();
  }

  /* MDMA interrupt initialization */
  /* MDMA_IRQn interrupt configuration */
  HAL_NVIC_SetPriority(MDMA_IRQn, 5, 0);
  HAL_NVIC_EnableIRQ(MDMA_IRQn);

}

/* FMC initialization function */
static void MX_FMC_Init(void)
{

  FMC_SDRAM_TimingTypeDef SdramTiming = {0};

  /** Perform the SDRAM1 memory initialization sequence
  */
  hsdram1.Instance = FMC_SDRAM_DEVICE;
  /* hsdram1.Init */
  hsdram1.Init.SDBank = FMC_SDRAM_BANK2;
  hsdram1.Init.ColumnBitsNumber = FMC_SDRAM_COLUMN_BITS_NUM_9;
  hsdram1.Init.RowBitsNumber = FMC_SDRAM_ROW_BITS_NUM_12;
  hsdram1.Init.MemoryDataWidth = FMC_SDRAM_MEM_BUS_WIDTH_16;
  hsdram1.Init.InternalBankNumber = FMC_SDRAM_INTERN_BANKS_NUM_4;
  hsdram1.Init.CASLatency = FMC_SDRAM_CAS_LATENCY_2;
  hsdram1.Init.WriteProtection = FMC_SDRAM_WRITE_PROTECTION_DISABLE;
  hsdram1.Init.SDClockPeriod = FMC_SDRAM_CLOCK_PERIOD_3;
  hsdram1.Init.ReadBurst = FMC_SDRAM_RBURST_ENABLE;
  hsdram1.Init.ReadPipeDelay = FMC_SDRAM_RPIPE_DELAY_2;
  /* SdramTiming */
  SdramTiming.LoadToActiveDelay = 2;
  SdramTiming.ExitSelfRefreshDelay = 7;
  SdramTiming.SelfRefreshTime = 4;
  SdramTiming.RowCycleDelay = 7;
  SdramTiming.WriteRecoveryTime = 3;
  SdramTiming.RPDelay = 2;
  SdramTiming.RCDDelay = 2;

  if (HAL_SDRAM_Init(&hsdram1, &SdramTiming) != HAL_OK)
  {
    Error_Handler( );
  }

}

static void MX_GPIO_Init(void)
{
  GPIO_InitTypeDef GPIO_InitStruct = {0};

  /* GPIO Ports Clock Enable */
  __HAL_RCC_GPIOG_CLK_ENABLE();
  __HAL_RCC_GPIOK_CLK_ENABLE();
  __HAL_RCC_GPIOD_CLK_ENABLE();
  __HAL_RCC_GPIOC_CLK_ENABLE();
  __HAL_RCC_GPIOE_CLK_ENABLE();
  __HAL_RCC_GPIOJ_CLK_ENABLE();
  __HAL_RCC_GPIOA_CLK_ENABLE();
  __HAL_RCC_GPIOH_CLK_ENABLE();
  __HAL_RCC_GPIOI_CLK_ENABLE();
  __HAL_RCC_GPIOB_CLK_ENABLE();
  __HAL_RCC_GPIOF_CLK_ENABLE();

  /*Configure GPIO pin Output Level */
  HAL_GPIO_WritePin(GPIOG, LED3_Pin|LED2_Pin, GPIO_PIN_SET);

  /*Configure GPIO pin Output Level */
  HAL_GPIO_WritePin(GPIOH, VSYNC_FREQ_Pin|RENDER_TIME_Pin|MCU_ACTIVE_Pin, GPIO_PIN_RESET);

  /*Configure GPIO pin Output Level */
  HAL_GPIO_WritePin(FRAME_RATE_GPIO_Port, FRAME_RATE_Pin, GPIO_PIN_RESET);

  /*Configure GPIO pin Output Level */
  HAL_GPIO_WritePin(GPIOA, LCD_BL_CTRL_Pin|LCD_ON_OFF_Pin, GPIO_PIN_RESET);

  /*Configure GPIO pins : LED3_Pin LED2_Pin */
  GPIO_InitStruct.Pin = LED3_Pin|LED2_Pin;
  GPIO_InitStruct.Mode = GPIO_MODE_OUTPUT_PP;
  GPIO_InitStruct.Pull = GPIO_NOPULL;
  GPIO_InitStruct.Speed = GPIO_SPEED_FREQ_LOW;
  HAL_GPIO_Init(GPIOG, &GPIO_InitStruct);

  /*Configure GPIO pins : VSYNC_FREQ_Pin RENDER_TIME_Pin MCU_ACTIVE_Pin */
  GPIO_InitStruct.Pin = VSYNC_FREQ_Pin|RENDER_TIME_Pin|MCU_ACTIVE_Pin;
  GPIO_InitStruct.Mode = GPIO_MODE_OUTPUT_PP;
  GPIO_InitStruct.Pull = GPIO_NOPULL;
  GPIO_InitStruct.Speed = GPIO_SPEED_FREQ_VERY_HIGH;
  HAL_GPIO_Init(GPIOH, &GPIO_InitStruct);

  /*Configure GPIO pin : PI8 */
  GPIO_InitStruct.Pin = GPIO_PIN_8;
  GPIO_InitStruct.Mode = GPIO_MODE_INPUT;
  GPIO_InitStruct.Pull = GPIO_PULLUP;
  HAL_GPIO_Init(GPIOI, &GPIO_InitStruct);

  /*Configure GPIO pin : FRAME_RATE_Pin */
  GPIO_InitStruct.Pin = FRAME_RATE_Pin;
  GPIO_InitStruct.Mode = GPIO_MODE_OUTPUT_PP;
  GPIO_InitStruct.Pull = GPIO_NOPULL;
  GPIO_InitStruct.Speed = GPIO_SPEED_FREQ_VERY_HIGH;
  HAL_GPIO_Init(FRAME_RATE_GPIO_Port, &GPIO_InitStruct);

  /*Configure GPIO pin : LCD_INT_Pin */
  GPIO_InitStruct.Pin = LCD_INT_Pin;
  GPIO_InitStruct.Mode = GPIO_MODE_IT_RISING;
  GPIO_InitStruct.Pull = GPIO_PULLUP;
  HAL_GPIO_Init(LCD_INT_GPIO_Port, &GPIO_InitStruct);

  /*Configure GPIO pin : LCD_BL_CTRL_Pin */
  GPIO_InitStruct.Pin = LCD_BL_CTRL_Pin;
  GPIO_InitStruct.Mode = GPIO_MODE_OUTPUT_PP;
  GPIO_InitStruct.Pull = GPIO_NOPULL;
  GPIO_InitStruct.Speed = GPIO_SPEED_FREQ_LOW;
  HAL_GPIO_Init(LCD_BL_CTRL_GPIO_Port, &GPIO_InitStruct);

  /*Configure GPIO pin : LCD_ON_OFF_Pin */
  GPIO_InitStruct.Pin = LCD_ON_OFF_Pin;
  GPIO_InitStruct.Mode = GPIO_MODE_OUTPUT_PP;
  GPIO_InitStruct.Pull = GPIO_PULLUP;
  GPIO_InitStruct.Speed = GPIO_SPEED_FREQ_LOW;
  HAL_GPIO_Init(LCD_ON_OFF_GPIO_Port, &GPIO_InitStruct);

  /* EXTI interrupt init*/
  HAL_NVIC_SetPriority(EXTI2_IRQn, 5, 0);
  HAL_NVIC_EnableIRQ(EXTI2_IRQn);

}

/* USER CODE BEGIN 4 */
static void SDRAM_Initialization_Sequence(SDRAM_HandleTypeDef *hsdram, FMC_SDRAM_CommandTypeDef *Command)
{
  __IO uint32_t tmpmrd =0;
  /* Step 1:  Configure a clock configuration enable command */
  Command->CommandMode = FMC_SDRAM_CMD_CLK_ENABLE;
  Command->CommandTarget = FMC_SDRAM_CMD_TARGET_BANK2;
  Command->AutoRefreshNumber = 1;
  Command->ModeRegisterDefinition = 0;

  /* Send the command */
  HAL_SDRAM_SendCommand(hsdram, Command, SDRAM_TIMEOUT);

  /* Step 2: Insert 100 us minimum delay */
  /* Inserted delay is equal to 1 ms due to systick time base unit (ms) */
  HAL_Delay(1);

  /* Step 3: Configure a PALL (precharge all) command */
  Command->CommandMode = FMC_SDRAM_CMD_PALL;
  Command->CommandTarget = FMC_SDRAM_CMD_TARGET_BANK2;
  Command->AutoRefreshNumber = 1;
  Command->ModeRegisterDefinition = 0;

  /* Send the command */
  HAL_SDRAM_SendCommand(hsdram, Command, SDRAM_TIMEOUT);

  /* Step 4 : Configure a Auto-Refresh command */
  Command->CommandMode = FMC_SDRAM_CMD_AUTOREFRESH_MODE;
  Command->CommandTarget = FMC_SDRAM_CMD_TARGET_BANK2;
  Command->AutoRefreshNumber = 8;
  Command->ModeRegisterDefinition = 0;

  /* Send the command */
  HAL_SDRAM_SendCommand(hsdram, Command, SDRAM_TIMEOUT);

  /* Step 5: Program the external memory mode register */
  tmpmrd = (uint32_t)SDRAM_MODEREG_BURST_LENGTH_1          |
                     SDRAM_MODEREG_BURST_TYPE_SEQUENTIAL   |
                     SDRAM_MODEREG_CAS_LATENCY_2           |
                     SDRAM_MODEREG_OPERATING_MODE_STANDARD |
                     SDRAM_MODEREG_WRITEBURST_MODE_SINGLE;

  Command->CommandMode = FMC_SDRAM_CMD_LOAD_MODE;
  Command->CommandTarget = FMC_SDRAM_CMD_TARGET_BANK2;
  Command->AutoRefreshNumber = 1;
  Command->ModeRegisterDefinition = tmpmrd;

  /* Send the command */
  HAL_SDRAM_SendCommand(hsdram, Command, SDRAM_TIMEOUT);

  /* Step 6: Set the refresh rate counter */
  /* Set the device refresh rate */
  HAL_SDRAM_ProgramRefreshRate(hsdram, REFRESH_COUNT);

}

/* USER CODE END 4 */

void StartDefaultTask(void *argument)
{
  /* USER CODE BEGIN 5 */

  /* Infinite loop */
  for(;;)
  {
    osDelay(100);
  }
  /* USER CODE END 5 */
}

 /* MPU Configuration */

void MPU_Config(void)
{
  MPU_Region_InitTypeDef MPU_InitStruct = {0};

  /* Disables the MPU */
  HAL_MPU_Disable();

  /** Initializes and configures the Region and the memory to be protected
  */
  MPU_InitStruct.Enable = MPU_REGION_ENABLE;
  MPU_InitStruct.Number = MPU_REGION_NUMBER0;
  MPU_InitStruct.BaseAddress = 0x90000000;
  MPU_InitStruct.Size = MPU_REGION_SIZE_256MB;
  MPU_InitStruct.SubRegionDisable = 0x0;
  MPU_InitStruct.TypeExtField = MPU_TEX_LEVEL0;
  MPU_InitStruct.AccessPermission = MPU_REGION_NO_ACCESS;
  MPU_InitStruct.DisableExec = MPU_INSTRUCTION_ACCESS_DISABLE;
  MPU_InitStruct.IsShareable = MPU_ACCESS_NOT_SHAREABLE;
  MPU_InitStruct.IsCacheable = MPU_ACCESS_NOT_CACHEABLE;
  MPU_InitStruct.IsBufferable = MPU_ACCESS_NOT_BUFFERABLE;

  HAL_MPU_ConfigRegion(&MPU_InitStruct);

  /** Initializes and configures the Region and the memory to be protected
  */
  MPU_InitStruct.Number = MPU_REGION_NUMBER1;
  MPU_InitStruct.Size = MPU_REGION_SIZE_64MB;
  MPU_InitStruct.AccessPermission = MPU_REGION_FULL_ACCESS;
  MPU_InitStruct.IsCacheable = MPU_ACCESS_CACHEABLE;

  HAL_MPU_ConfigRegion(&MPU_InitStruct);

  /** Initializes and configures the Region and the memory to be protected
  */
  MPU_InitStruct.Number = MPU_REGION_NUMBER2;
  MPU_InitStruct.BaseAddress = 0x24000000;
  MPU_InitStruct.Size = MPU_REGION_SIZE_1MB;

  HAL_MPU_ConfigRegion(&MPU_InitStruct);

  /** Initializes and configures the Region and the memory to be protected
  */
  MPU_InitStruct.Number = MPU_REGION_NUMBER3;
  MPU_InitStruct.Size = MPU_REGION_SIZE_256KB;
  MPU_InitStruct.IsBufferable = MPU_ACCESS_BUFFERABLE;

  HAL_MPU_ConfigRegion(&MPU_InitStruct);
  /* Enables the MPU */
  HAL_MPU_Enable(MPU_PRIVILEGED_DEFAULT);

}

void HAL_TIM_PeriodElapsedCallback(TIM_HandleTypeDef *htim)
{
  if (htim->Instance == TIM6) {
    HAL_IncTick();
  }
}

void Error_Handler(void)
{
  /* USER CODE BEGIN Error_Handler_Debug */
  /* User can add his own implementation to report the HAL error return state */

	while(1)
	{
		// Optionally, you can flash an LED or send a debug message here
		        HAL_GPIO_TogglePin(GPIOG, GPIO_PIN_2); // Example: Toggle LED to indicate error
		        HAL_Delay(500); // Delay for a while
	}
  /* USER CODE END Error_Handler_Debug */
}
